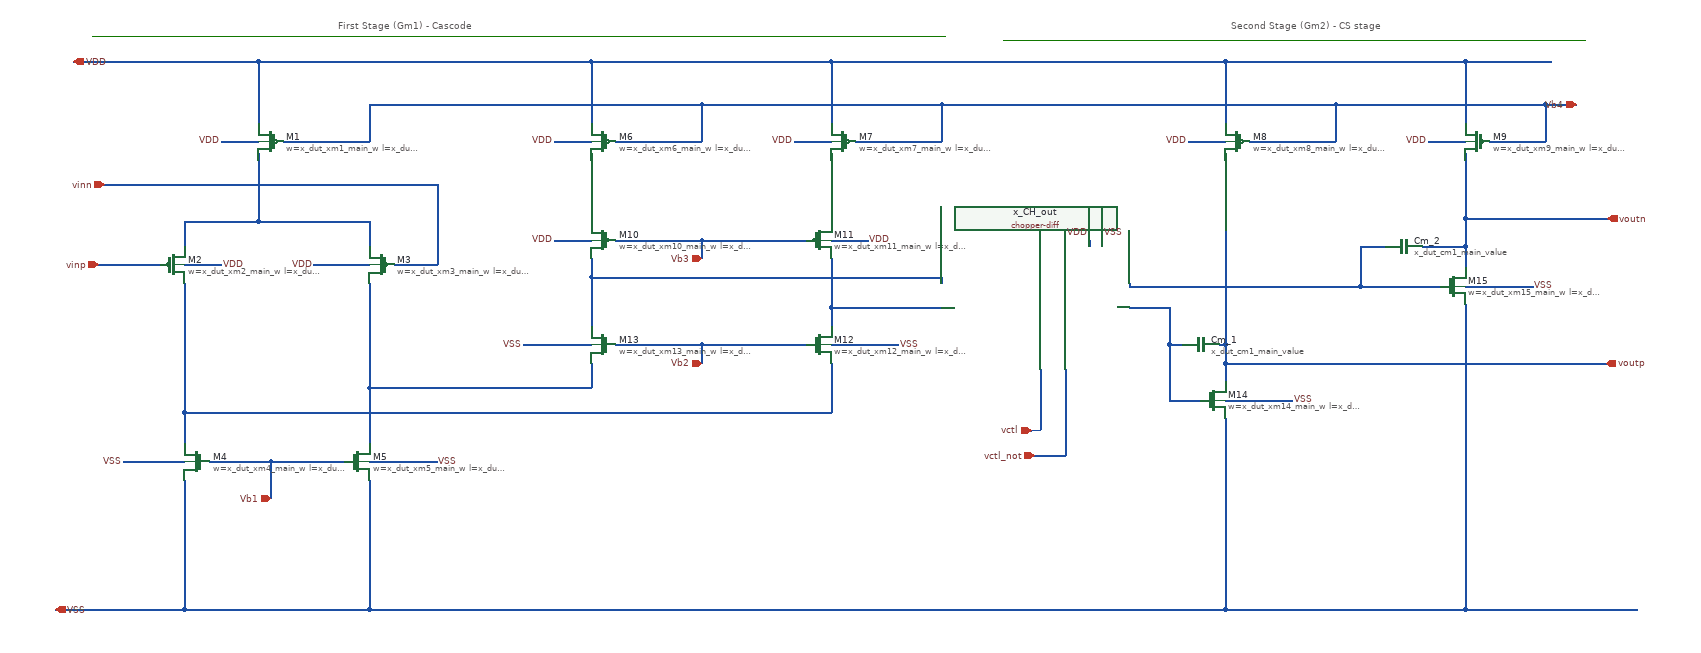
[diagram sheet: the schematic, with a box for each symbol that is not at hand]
v {xschem version=3.4.5 file_version=1.2
}
G {}
K {}
V {}
S {}
E {}
L 4 1600 -1035 2545 -1035 {}
L 4 120 -1040 1505 -1040 {}
T {First Stage (Gm1) - Cascode} 520 -1070 0 0 0.4 0.4 {}
T {Second Stage (Gm2) - CS stage} 1970 -1070 0 0 0.4 0.4 {}
N 270 -740 390 -740 {
lab=#net1}
N 270 -740 270 -700 {
lab=#net1}
N 390 -740 570 -740 {
lab=#net1}
N 570 -740 570 -700 {
lab=#net1}
N 390 -850 390 -740 {
lab=#net1}
N 610 -670 680 -670 {
lab=vinn}
N 680 -800 680 -670 {
lab=vinn}
N 140 -800 680 -800 {
lab=vinn}
N 130 -670 230 -670 {
lab=vinp}
N 270 -670 330 -670 {
lab=VDD}
N 480 -670 570 -670 {
lab=VDD}
N 330 -870 390 -870 {
lab=VDD}
N 430 -870 570 -870 {
lab=Vb4}
N 1320 -1000 1960 -1000 {
lab=VDD}
N 2350 -110 2630 -110 {
lab=VSS}
N 270 -430 270 -380 {
lab=#net2}
N 390 -1000 390 -900 {
lab=VDD}
N 90 -1000 390 -1000 {
lab=VDD}
N 570 -470 570 -380 {
lab=#net3}
N 410 -350 530 -350 {
lab=Vb1}
N 270 -320 270 -110 {
lab=VSS}
N 60 -110 270 -110 {
lab=VSS}
N 570 -320 570 -110 {
lab=VSS}
N 270 -110 570 -110 {
lab=VSS}
N 170 -350 270 -350 {
lab=VSS}
N 570 -350 680 -350 {
lab=VSS}
N 930 -850 930 -740 {
lab=#net4}
N 870 -870 930 -870 {
lab=VDD}
N 970 -870 1110 -870 {
lab=Vb4}
N 930 -1000 930 -900 {
lab=VDD}
N 390 -1000 930 -1000 {
lab=VDD}
N 1320 -850 1320 -740 {
lab=#net5}
N 1260 -870 1320 -870 {
lab=VDD}
N 1360 -870 1500 -870 {
lab=Vb4}
N 1320 -1000 1320 -900 {
lab=VDD}
N 930 -1000 1320 -1000 {
lab=VDD}
N 1960 -510 1960 -480 {
lab=voutp}
N 1900 -870 1960 -870 {
lab=VDD}
N 2000 -870 2140 -870 {
lab=Vb4}
N 1960 -1000 1960 -900 {
lab=VDD}
N 2290 -870 2350 -870 {
lab=VDD}
N 2480 -930 2530 -930 {
lab=Vb4}
N 2350 -1000 2350 -900 {
lab=VDD}
N 1960 -1000 2350 -1000 {
lab=VDD}
N 2350 -1000 2490 -1000 {
lab=VDD}
N 2480 -930 2480 -870 {
lab=Vb4}
N 2390 -870 2480 -870 {
lab=Vb4}
N 2140 -930 2480 -930 {
lab=Vb4}
N 2140 -930 2140 -870 {
lab=Vb4}
N 1500 -930 2140 -930 {
lab=Vb4}
N 1500 -930 1500 -870 {
lab=Vb4}
N 1110 -930 1500 -930 {
lab=Vb4}
N 1110 -930 1110 -870 {
lab=Vb4}
N 570 -930 1110 -930 {
lab=Vb4}
N 570 -930 570 -870 {
lab=Vb4}
N 870 -710 930 -710 {
lab=VDD}
N 1320 -710 1380 -710 {
lab=VDD}
N 1110 -710 1280 -710 {
lab=Vb3}
N 1320 -540 1430 -540 {
lab=VSS}
N 820 -540 930 -540 {
lab=VSS}
N 1320 -600 1320 -570 {
lab=#net6}
N 930 -650 930 -570 {
lab=#net7}
N 1110 -540 1280 -540 {
lab=Vb2}
N 1320 -510 1320 -430 {
lab=#net2}
N 270 -430 1320 -430 {
lab=#net2}
N 270 -640 270 -430 {
lab=#net2}
N 930 -510 930 -470 {
lab=#net3}
N 570 -470 930 -470 {
lab=#net3}
N 570 -640 570 -470 {
lab=#net3}
N 410 -350 410 -290 {
lab=Vb1}
N 310 -350 410 -350 {
lab=Vb1}
N 1110 -540 1110 -510 {
lab=Vb2}
N 970 -540 1110 -540 {
lab=Vb2}
N 1110 -710 1110 -680 {
lab=Vb3}
N 970 -710 1110 -710 {
lab=Vb3}
N 1320 -600 1500 -600 {
lab=#net6}
N 1320 -680 1320 -600 {
lab=#net6}
N 930 -650 1500 -650 {
lab=#net7}
N 930 -680 930 -650 {
lab=#net7}
N 1960 -450 2070 -450 {
lab=VSS}
N 2350 -635 2460 -635 {
lab=VSS}
N 1960 -110 2350 -110 {
lab=VSS}
N 1960 -420 1960 -110 {
lab=VSS}
N 570 -110 1960 -110 {
lab=VSS}
N 1870 -450 1920 -450 {
lab=#net8}
N 1870 -540 1870 -450 {
lab=#net8}
N 1805 -600 1870 -600 {
lab=#net8}
N 1870 -540 1890 -540 {
lab=#net8}
N 1870 -600 1870 -540 {
lab=#net8}
N 1950 -540 1960 -540 {
lab=voutp}
N 1960 -850 1960 -540 {
lab=voutp}
N 1805 -635 2180 -635 {
lab=#net9}
N 2180 -700 2180 -635 {
lab=#net9}
N 2180 -635 2310 -635 {
lab=#net9}
N 2180 -700 2220 -700 {
lab=#net9}
N 2280 -700 2350 -700 {
lab=voutn}
N 2350 -745 2350 -700 {
lab=voutn}
N 2350 -745 2581.25 -745 {
lab=voutn}
N 1960 -510 2580 -510 {
lab=voutp}
N 1960 -540 1960 -510 {
lab=voutp}
N 1500 -650 1500 -640 {
lab=#net7}
N 1805 -640 1805 -635 {
lab=#net9}
N 1660 -500 1660 -402.5 {
lab=vctl}
N 1645 -401.25 1660 -402.5 {
lab=vctl}
N 1650 -360 1700 -360 {
lab=vctl_not}
N 1700 -500 1700 -360 {
lab=vctl_not}
N 1738.75 -721.25 1740 -700 {
lab=VDD}
N 1760 -700 1761.25 -721.25 {
lab=VSS}
N 2350 -850 2350 -745 {
lab=voutn}
N 2350 -700 2350 -665 {
lab=voutn}
N 2350 -605 2350 -110 {
lab=VSS}
C {devices/title.sym} 190 -50 0 0 {name=l5 author="Copyright 2026 MacAnalog Research Group"}
C {iopin.sym} 90 -1000 0 1 {name=p1 lab=VDD}
C {iopin.sym} 60 -110 0 1 {name=p5 lab=VSS}
C {sg13g2_pr/sg13_lv_pmos.sym} 410 -870 0 1 {name=M1
l=x_dut_xm1_main_l
w=x_dut_xm1_main_w
ng=1
m=1
model=sg13_lv_pmos
spiceprefix=X
}
C {sg13g2_pr/sg13_lv_pmos.sym} 250 -670 0 0 {name=M2
l=x_dut_xm2_main_l
w=x_dut_xm2_main_w
ng=1
m=1
model=sg13_lv_pmos
spiceprefix=X
}
C {sg13g2_pr/sg13_lv_pmos.sym} 590 -670 0 1 {name=M3
l=x_dut_xm3_main_l
w=x_dut_xm3_main_w
ng=1
m=1
model=sg13_lv_pmos
spiceprefix=X
}
C {iopin.sym} 2530 -930 0 0 {name=p2 lab=Vb4}
C {ipin.sym} 130 -670 0 0 {name=p3 lab=vinp}
C {ipin.sym} 140 -800 0 0 {name=p4 lab=vinn}
C {lab_pin.sym} 330 -670 0 1 {name=p8 sig_type=std_logic lab=VDD}
C {lab_pin.sym} 480 -670 0 0 {name=p9 sig_type=std_logic lab=VDD}
C {lab_pin.sym} 330 -870 0 0 {name=p10 sig_type=std_logic lab=VDD}
C {sg13g2_pr/sg13_lv_nmos.sym} 290 -350 0 1 {name=M4
l=x_dut_xm4_main_l
w=x_dut_xm4_main_w
ng=1
m=1
model=sg13_lv_nmos
spiceprefix=X
}
C {sg13g2_pr/sg13_lv_nmos.sym} 550 -350 0 0 {name=M5
l=x_dut_xm5_main_l
w=x_dut_xm5_main_w
ng=1
m=1
model=sg13_lv_nmos
spiceprefix=X
}
C {lab_pin.sym} 680 -350 0 1 {name=p6 sig_type=std_logic lab=VSS}
C {lab_pin.sym} 170 -350 0 0 {name=p7 sig_type=std_logic lab=VSS}
C {sg13g2_pr/sg13_lv_pmos.sym} 950 -870 0 1 {name=M6
l=x_dut_xm6_main_l
w=x_dut_xm6_main_w
ng=1
m=1
model=sg13_lv_pmos
spiceprefix=X
}
C {lab_pin.sym} 870 -870 0 0 {name=p11 sig_type=std_logic lab=VDD}
C {sg13g2_pr/sg13_lv_pmos.sym} 1340 -870 0 1 {name=M7
l=x_dut_xm7_main_l
w=x_dut_xm7_main_w
ng=1
m=1
model=sg13_lv_pmos
spiceprefix=X
}
C {lab_pin.sym} 1260 -870 0 0 {name=p12 sig_type=std_logic lab=VDD}
C {sg13g2_pr/sg13_lv_pmos.sym} 1980 -870 0 1 {name=M8
l=x_dut_xm8_main_l
w=x_dut_xm8_main_w
ng=1
m=1
model=sg13_lv_pmos
spiceprefix=X
}
C {lab_pin.sym} 1900 -870 0 0 {name=p13 sig_type=std_logic lab=VDD}
C {sg13g2_pr/sg13_lv_pmos.sym} 2370 -870 0 1 {name=M9
l=x_dut_xm9_main_l
w=x_dut_xm9_main_w
ng=1
m=1
model=sg13_lv_pmos
spiceprefix=X
}
C {lab_pin.sym} 2290 -870 0 0 {name=p14 sig_type=std_logic lab=VDD}
C {sg13g2_pr/sg13_lv_pmos.sym} 950 -710 0 1 {name=M10
l=x_dut_xm10_main_l
w=x_dut_xm10_main_w
ng=1
m=1
model=sg13_lv_pmos
spiceprefix=X
}
C {lab_pin.sym} 870 -710 0 0 {name=p15 sig_type=std_logic lab=VDD}
C {sg13g2_pr/sg13_lv_pmos.sym} 1300 -710 0 0 {name=M11
l=x_dut_xm11_main_l
w=x_dut_xm11_main_w
ng=1
m=1
model=sg13_lv_pmos
spiceprefix=X
}
C {lab_pin.sym} 1380 -710 0 1 {name=p16 sig_type=std_logic lab=VDD}
C {sg13g2_pr/sg13_lv_nmos.sym} 1300 -540 0 0 {name=M12
l=x_dut_xm12_main_l
w=x_dut_xm12_main_w
ng=1
m=1
model=sg13_lv_nmos
spiceprefix=X
}
C {lab_pin.sym} 1430 -540 0 1 {name=p17 sig_type=std_logic lab=VSS}
C {sg13g2_pr/sg13_lv_nmos.sym} 950 -540 0 1 {name=M13
l=x_dut_xm13_main_l
w=x_dut_xm13_main_w
ng=1
m=1
model=sg13_lv_nmos
spiceprefix=X
}
C {lab_pin.sym} 820 -540 0 0 {name=p18 sig_type=std_logic lab=VSS}
C {iopin.sym} 1110 -680 0 0 {name=p19 lab=Vb3}
C {iopin.sym} 1110 -510 0 0 {name=p20 lab=Vb2}
C {iopin.sym} 410 -290 0 0 {name=p21 lab=Vb1}
C {shared/chopper-diff.sym} 1520 -520 0 0 {name=x_CH_out}
C {sg13g2_pr/sg13_lv_nmos.sym} 1940 -450 0 0 {name=M14
l=x_dut_xm14_main_l
w=x_dut_xm14_main_w
ng=1
m=1
model=sg13_lv_nmos
spiceprefix=X
}
C {lab_pin.sym} 2070 -450 0 1 {name=p22 sig_type=std_logic lab=VSS}
C {sg13g2_pr/sg13_lv_nmos.sym} 2330 -635 0 0 {name=M15
l=x_dut_xm15_main_l
w=x_dut_xm15_main_w
ng=1
m=1
model=sg13_lv_nmos
spiceprefix=X
}
C {lab_pin.sym} 2460 -635 0 1 {name=p23 sig_type=std_logic lab=VSS}
C {capa.sym} 1920 -540 3 0 {name=Cm_1
m=1
value=x_dut_cm1_main_value
footprint=1206
device="ceramic capacitor"}
C {lab_pin.sym} 1738.75 -721.25 0 0 {name=p24 sig_type=std_logic lab=VDD}
C {lab_pin.sym} 1761.25 -721.25 0 1 {name=p25 sig_type=std_logic lab=VSS}
C {capa.sym} 2250 -700 3 0 {name=Cm_2
m=1
value=x_dut_cm1_main_value
footprint=1206
device="ceramic capacitor"}
C {opin.sym} 2581.25 -745 0 0 {name=p26 lab=voutn}
C {opin.sym} 2578.75 -510 0 0 {name=p27 lab=voutp}
C {ipin.sym} 1650 -360 0 0 {name=p28 lab=vctl_not}
C {ipin.sym} 1645 -401.25 0 0 {name=p29 lab=vctl}
